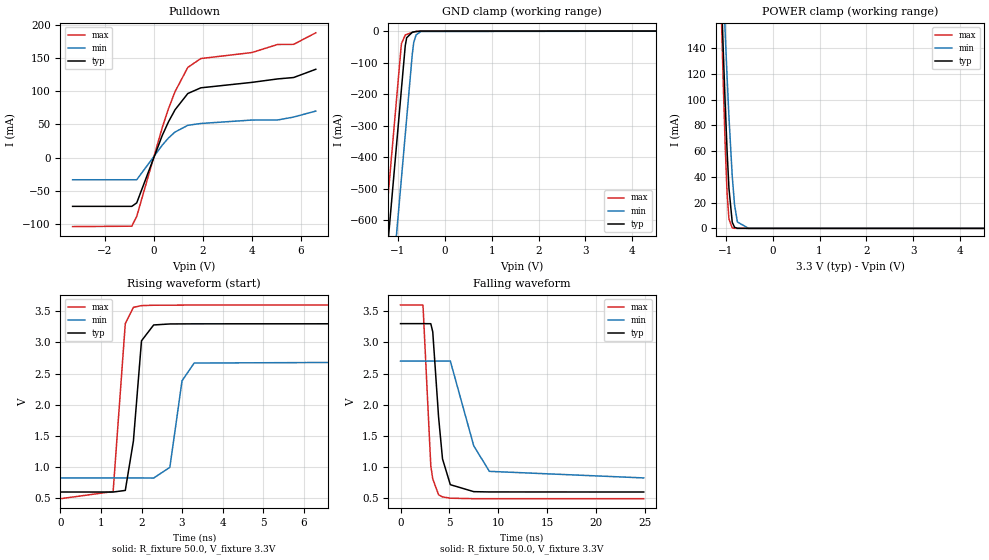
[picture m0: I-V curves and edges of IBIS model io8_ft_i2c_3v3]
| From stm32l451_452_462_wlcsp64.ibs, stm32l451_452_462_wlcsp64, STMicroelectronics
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[Model]   io8_ft_i2c_3v3
Model_type I/O_open_drain
Polarity   Non-Inverting
Enable   Active-Low
| CAP_THRESHOLD on pad IOFT is "UDTCAPC" :
| Rising=30.00f vddiom   Falling=70.00f vddiom
| C_comp min and max val. don't necessarily correlate with the min and max pvt
| but are the smallest and greatest pad capacitance found.
| var   typ   min   max
C_comp   2.52235pF  2.49685pF  2.96493pF
|C_comp_pulldown   2.52235pF  2.49685pF  2.96493pF
Vinl = 810.0mV
Vinh = 2.52V
Vmeas = 1.65V   | Reference voltage for timing measurements
Cref  = 50.0pF   | Timing specification test load capacitance value
Rref  = 100.0MOhm   | Timing specification test load resistance value
Vref  = 2.65V   | Timing specification test load voltage
[Model Spec]
| TIME_THRESHOLD on pin ZIV12 is "CMOS" :
| Rising=50.00f vdd   Falling=50.00f vdd
Vinl 1.34770V 1.11470V 1.44970V
Vinh 1.77530V 1.49030V 1.90330V
| variable   typ   min   max
[Temperature Range] 25.0 140.0 -40.0
| variable   typ   min   max
[Voltage Range] 3.3V 2.7V 3.6V
| variable   typ   min   max
[POWER Clamp Reference] 3.3V 2.7V 3.6V
| variable   typ   min   max
[GND Clamp Reference] 0V 0V 0V
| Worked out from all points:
|   slope of the pulldown table from 0 to 0.495 V, typ, clamps not added: 10.9 ohm
|   GND clamp passes 1 mA (typ) near -0.58 V on its own axis
|   POWER clamp passes 1 mA (typ) near -0.81 V on its own axis
|   rising waveform, R_fixture 50.0, V_fixture 3.3V: 20-80 % time 195ps typ, 223ps min, 189ps max; typ from 0.603 V to 3.3 V
|   falling waveform, R_fixture 50.0, V_fixture 3.3V: 20-80 % time 799ps typ, 1.78ns min, 529ps max; typ from 3.3 V to 0.603 V
[POWER Clamp]
-3.3V     2.991A     2.546A     3.694A
-1.11V    202.2mA    242.3mA    190.9mA
-1.09V    180mA      223.6mA    163.4mA
-1.05V    136.9mA    187mA      110.9mA
-1.01V    96.55mA    151.6mA    64.02mA
-970mV    60.39mA    117.9mA    27.41mA
-930mV    31.08mA    86.54mA    7.282mA
-860mV    4.779mA    40.5mA     315.2uA
-810mV    823.2uA    18.15mA    29.21uA
-750mV    88.98uA    4.952mA    1.667uA
-510mV    11.25nA    8.405uA    49.81pA
6.6V      0A         0A         0A
[GND Clamp]
-3.3V     -4.227A    -4.51A     -4.082A
-1.38V    -963.2mA   -1.246A    -818.4mA
-1.21V    -674.2mA   -957.3mA   -529.4mA
-930mV    -198.2mA   -481.3mA   -53.39mA
-920mV    -181.2mA   -464.3mA   -39.67mA
-840mV    -46.53mA   -328.3mA   -12.86mA
-810mV    -21.49mA   -277.3mA   -10.68mA
-690mV    -3.888mA   -73.32mA   -4.338mA
-660mV    -2.829mA   -36.82mA   -3.141mA
-610mV    -1.53mA    -12.7mA    -1.582mA
-510mV    -241uA     -1.605mA   -174.9uA
6.6V      840.6pA    198.7nA    588.9pA
| variable   typ   min   max
[Pullup Reference] 3.3V 2.7V 3.6V
| variable   typ   min   max
[Pulldown Reference] 0V 0V 0V
[Pulldown]
-3.3V     -73.23mA   -33.2mA    -103.7mA
-890mV    -73.23mA   -33.2mA    -103.1mA
-690mV    -68.03mA   -33.2mA    -88.43mA
350mV     33.51mA    18.84mA    45.34mA
600mV     53.75mA    29.58mA    73.34mA
870mV     72.1mA     38.65mA    99.39mA
1.39V     96.62mA    48.75mA    135.9mA
1.92V     105.2mA    51.51mA    149.3mA
4V        113.4mA    56.69mA    158.3mA
5.05V     118.6mA    56.8mA     170.5mA
5.7V      120.7mA    61.2mA     170.6mA
6.6V      133.1mA    70.2mA     188mA
[Ramp]
dV/dt_r 1.61788V/169.09446ps 1.12287V/208.68167ps 1.86269V/163.07504ps
dV/dt_f 1.61846V/797.23392ps 1.12294V/1.78104ns 1.86272V/522.32836ps
R_load = 50.0
| Removed startup time: 0s 0s 0s  .
| Removed end time: 14.9ns.
[Rising Waveform]
R_fixture   = 50.0
V_fixture   = 3.3V
V_fixture_min = 2.7V
V_fixture_max = 3.6V
0s        602.6mV    828.4mV    495.5mV
1.3ns     602.2mV    828.3mV    610.1mV
1.6ns     628.2mV    828.3mV    3.301V
1.8ns     1.418V     828.3mV    3.561V
2ns       3.025V     828mV      3.589V
2.3ns     3.279V     826.2mV    3.595V
2.7ns     3.295V     997.8mV    3.596V
3ns       3.296V     2.384V     3.597V
3.3ns     3.297V     2.669V     3.598V
14.9ns    3.3V       2.7V       3.6V
| Removed startup time: 0s 0s 0s  .
| Removed end time: 24.9ns.
[Falling Waveform]
R_fixture   = 50.0
V_fixture   = 3.3V
V_fixture_min = 2.7V
V_fixture_max = 3.6V
0s        3.3V       2.7V       3.6V
2.3ns     3.3V       2.7V       3.597V
3.1ns     3.299V     2.7V       1.022V
3.3ns     3.169V     2.7V       812.8mV
3.9ns     1.798V     2.7V       557.8mV
4.3ns     1.133V     2.7V       524.4mV
5.1ns     720mV      2.701V     503.4mV
7.5ns     608.4mV    1.342V     495.8mV
9.1ns     603.6mV    933.6mV    495.5mV
24.9ns    602.6mV    828.4mV    495.5mV
